VERSION 5.8 ;
BUSBITCHARS "[]" ;
DIVIDERCHAR "/" ;
UNITS
    DATABASE MICRONS 1000 ;
END UNITS

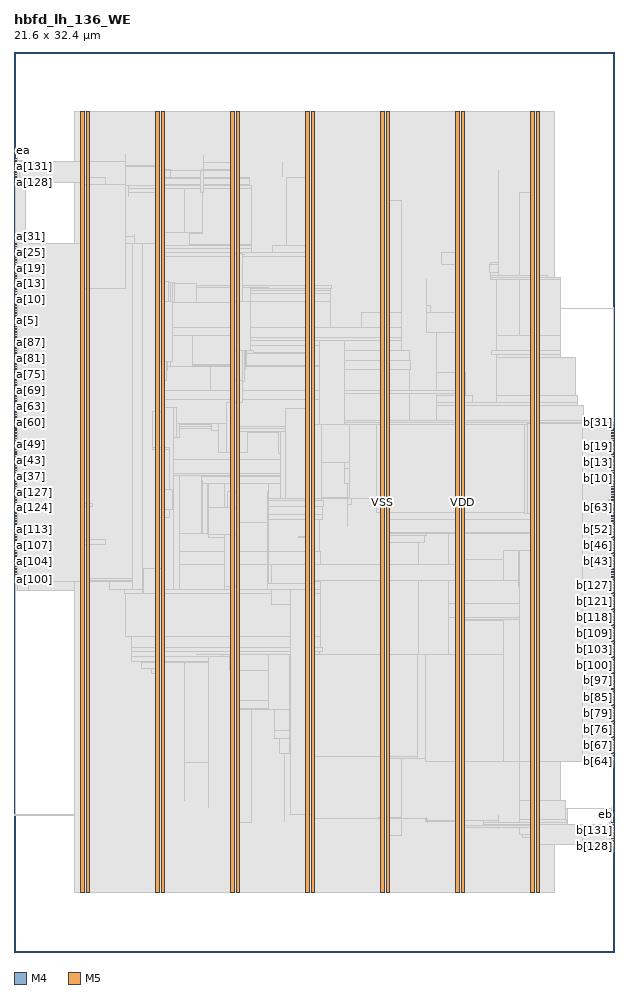
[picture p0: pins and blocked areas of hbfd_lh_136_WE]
MACRO hbfd_lh_136_WE
  FOREIGN hbfd_lh_136_WE 0 0 ;
  CLASS BLOCK ;
  SIZE 21.6 BY 32.4 ;
  PIN a[0]
    DIRECTION INPUT ;
    USE SIGNAL ;
    PORT
      LAYER M4 ;
        RECT  0 22.512 0.084 22.536 ;
    END
  END a[0]
  PIN a[100]
    DIRECTION INPUT ;
    USE SIGNAL ;
    PORT
      LAYER M4 ;
        RECT  0 13.68 0.084 13.704 ;
    END
  END a[100]
  PIN a[101]
    DIRECTION INPUT ;
    USE SIGNAL ;
    PORT
      LAYER M4 ;
        RECT  0 13.776 0.084 13.8 ;
    END
  END a[101]
  PIN a[102]
    DIRECTION INPUT ;
    USE SIGNAL ;
    PORT
      LAYER M4 ;
        RECT  0 13.872 0.084 13.896 ;
    END
  END a[102]
  PIN a[103]
    DIRECTION INPUT ;
    USE SIGNAL ;
    PORT
      LAYER M4 ;
        RECT  0 13.968 0.084 13.992 ;
    END
  END a[103]
  PIN a[104]
    DIRECTION INPUT ;
    USE SIGNAL ;
    PORT
      LAYER M4 ;
        RECT  0 14.064 0.084 14.088 ;
    END
  END a[104]
  PIN a[105]
    DIRECTION INPUT ;
    USE SIGNAL ;
    PORT
      LAYER M4 ;
        RECT  0 14.16 0.084 14.184 ;
    END
  END a[105]
  PIN a[106]
    DIRECTION INPUT ;
    USE SIGNAL ;
    PORT
      LAYER M4 ;
        RECT  0 14.256 0.084 14.28 ;
    END
  END a[106]
  PIN a[107]
    DIRECTION INPUT ;
    USE SIGNAL ;
    PORT
      LAYER M4 ;
        RECT  0 14.352 0.084 14.376 ;
    END
  END a[107]
  PIN a[108]
    DIRECTION INPUT ;
    USE SIGNAL ;
    PORT
      LAYER M4 ;
        RECT  0 14.448 0.084 14.472 ;
    END
  END a[108]
  PIN a[109]
    DIRECTION INPUT ;
    USE SIGNAL ;
    PORT
      LAYER M4 ;
        RECT  0 14.544 0.084 14.568 ;
    END
  END a[109]
  PIN a[10]
    DIRECTION INPUT ;
    USE SIGNAL ;
    PORT
      LAYER M4 ;
        RECT  0 23.472 0.084 23.496 ;
    END
  END a[10]
  PIN a[110]
    DIRECTION INPUT ;
    USE SIGNAL ;
    PORT
      LAYER M4 ;
        RECT  0 14.64 0.084 14.664 ;
    END
  END a[110]
  PIN a[111]
    DIRECTION INPUT ;
    USE SIGNAL ;
    PORT
      LAYER M4 ;
        RECT  0 14.736 0.084 14.76 ;
    END
  END a[111]
  PIN a[112]
    DIRECTION INPUT ;
    USE SIGNAL ;
    PORT
      LAYER M4 ;
        RECT  0 14.832 0.084 14.856 ;
    END
  END a[112]
  PIN a[113]
    DIRECTION INPUT ;
    USE SIGNAL ;
    PORT
      LAYER M4 ;
        RECT  0 14.928 0.084 14.952 ;
    END
  END a[113]
  PIN a[114]
    DIRECTION INPUT ;
    USE SIGNAL ;
    PORT
      LAYER M4 ;
        RECT  0 15.024 0.084 15.048 ;
    END
  END a[114]
  PIN a[115]
    DIRECTION INPUT ;
    USE SIGNAL ;
    PORT
      LAYER M4 ;
        RECT  0 15.12 0.084 15.144 ;
    END
  END a[115]
  PIN a[116]
    DIRECTION INPUT ;
    USE SIGNAL ;
    PORT
      LAYER M4 ;
        RECT  0 15.216 0.084 15.24 ;
    END
  END a[116]
  PIN a[117]
    DIRECTION INPUT ;
    USE SIGNAL ;
    PORT
      LAYER M4 ;
        RECT  0 15.312 0.084 15.336 ;
    END
  END a[117]
  PIN a[118]
    DIRECTION INPUT ;
    USE SIGNAL ;
    PORT
      LAYER M4 ;
        RECT  0 15.408 0.084 15.432 ;
    END
  END a[118]
  PIN a[119]
    DIRECTION INPUT ;
    USE SIGNAL ;
    PORT
      LAYER M4 ;
        RECT  0 15.504 0.084 15.528 ;
    END
  END a[119]
  PIN a[11]
    DIRECTION INPUT ;
    USE SIGNAL ;
    PORT
      LAYER M4 ;
        RECT  0 23.568 0.084 23.592 ;
    END
  END a[11]
  PIN a[120]
    DIRECTION INPUT ;
    USE SIGNAL ;
    PORT
      LAYER M4 ;
        RECT  0 15.6 0.084 15.624 ;
    END
  END a[120]
  PIN a[121]
    DIRECTION INPUT ;
    USE SIGNAL ;
    PORT
      LAYER M4 ;
        RECT  0 15.696 0.084 15.72 ;
    END
  END a[121]
  PIN a[122]
    DIRECTION INPUT ;
    USE SIGNAL ;
    PORT
      LAYER M4 ;
        RECT  0 15.792 0.084 15.816 ;
    END
  END a[122]
  PIN a[123]
    DIRECTION INPUT ;
    USE SIGNAL ;
    PORT
      LAYER M4 ;
        RECT  0 15.888 0.084 15.912 ;
    END
  END a[123]
  PIN a[124]
    DIRECTION INPUT ;
    USE SIGNAL ;
    PORT
      LAYER M4 ;
        RECT  0 15.984 0.084 16.008 ;
    END
  END a[124]
  PIN a[125]
    DIRECTION INPUT ;
    USE SIGNAL ;
    PORT
      LAYER M4 ;
        RECT  0 16.08 0.084 16.104 ;
    END
  END a[125]
  PIN a[126]
    DIRECTION INPUT ;
    USE SIGNAL ;
    PORT
      LAYER M4 ;
        RECT  0 16.176 0.084 16.2 ;
    END
  END a[126]
  PIN a[127]
    DIRECTION INPUT ;
    USE SIGNAL ;
    PORT
      LAYER M4 ;
        RECT  0 16.272 0.084 16.296 ;
    END
  END a[127]
  PIN a[128]
    DIRECTION INPUT ;
    USE SIGNAL ;
    PORT
      LAYER M4 ;
        RECT  0 27.696 0.084 27.72 ;
    END
  END a[128]
  PIN a[129]
    DIRECTION INPUT ;
    USE SIGNAL ;
    PORT
      LAYER M4 ;
        RECT  0 27.792 0.084 27.816 ;
    END
  END a[129]
  PIN a[12]
    DIRECTION INPUT ;
    USE SIGNAL ;
    PORT
      LAYER M4 ;
        RECT  0 23.664 0.084 23.688 ;
    END
  END a[12]
  PIN a[130]
    DIRECTION INPUT ;
    USE SIGNAL ;
    PORT
      LAYER M4 ;
        RECT  0 27.888 0.084 27.912 ;
    END
  END a[130]
  PIN a[131]
    DIRECTION INPUT ;
    USE SIGNAL ;
    PORT
      LAYER M4 ;
        RECT  0 27.984 0.084 28.008 ;
    END
  END a[131]
  PIN a[132]
    DIRECTION INPUT ;
    USE SIGNAL ;
    PORT
      LAYER M4 ;
        RECT  0 28.08 0.084 28.104 ;
    END
  END a[132]
  PIN a[133]
    DIRECTION INPUT ;
    USE SIGNAL ;
    PORT
      LAYER M4 ;
        RECT  0 28.176 0.084 28.2 ;
    END
  END a[133]
  PIN a[134]
    DIRECTION INPUT ;
    USE SIGNAL ;
    PORT
      LAYER M4 ;
        RECT  0 28.272 0.084 28.296 ;
    END
  END a[134]
  PIN a[135]
    DIRECTION INPUT ;
    USE SIGNAL ;
    PORT
      LAYER M4 ;
        RECT  0 28.368 0.084 28.392 ;
    END
  END a[135]
  PIN a[13]
    DIRECTION INPUT ;
    USE SIGNAL ;
    PORT
      LAYER M4 ;
        RECT  0 23.76 0.084 23.784 ;
    END
  END a[13]
  PIN a[14]
    DIRECTION INPUT ;
    USE SIGNAL ;
    PORT
      LAYER M4 ;
        RECT  0 23.856 0.084 23.88 ;
    END
  END a[14]
  PIN a[15]
    DIRECTION INPUT ;
    USE SIGNAL ;
    PORT
      LAYER M4 ;
        RECT  0 23.952 0.084 23.976 ;
    END
  END a[15]
  PIN a[16]
    DIRECTION INPUT ;
    USE SIGNAL ;
    PORT
      LAYER M4 ;
        RECT  0 24.048 0.084 24.072 ;
    END
  END a[16]
  PIN a[17]
    DIRECTION INPUT ;
    USE SIGNAL ;
    PORT
      LAYER M4 ;
        RECT  0 24.144 0.084 24.168 ;
    END
  END a[17]
  PIN a[18]
    DIRECTION INPUT ;
    USE SIGNAL ;
    PORT
      LAYER M4 ;
        RECT  0 24.24 0.084 24.264 ;
    END
  END a[18]
  PIN a[19]
    DIRECTION INPUT ;
    USE SIGNAL ;
    PORT
      LAYER M4 ;
        RECT  0 24.336 0.084 24.36 ;
    END
  END a[19]
  PIN a[1]
    DIRECTION INPUT ;
    USE SIGNAL ;
    PORT
      LAYER M4 ;
        RECT  0 22.608 0.084 22.632 ;
    END
  END a[1]
  PIN a[20]
    DIRECTION INPUT ;
    USE SIGNAL ;
    PORT
      LAYER M4 ;
        RECT  0 24.432 0.084 24.456 ;
    END
  END a[20]
  PIN a[21]
    DIRECTION INPUT ;
    USE SIGNAL ;
    PORT
      LAYER M4 ;
        RECT  0 24.528 0.084 24.552 ;
    END
  END a[21]
  PIN a[22]
    DIRECTION INPUT ;
    USE SIGNAL ;
    PORT
      LAYER M4 ;
        RECT  0 24.624 0.084 24.648 ;
    END
  END a[22]
  PIN a[23]
    DIRECTION INPUT ;
    USE SIGNAL ;
    PORT
      LAYER M4 ;
        RECT  0 24.72 0.084 24.744 ;
    END
  END a[23]
  PIN a[24]
    DIRECTION INPUT ;
    USE SIGNAL ;
    PORT
      LAYER M4 ;
        RECT  0 24.816 0.084 24.84 ;
    END
  END a[24]
  PIN a[25]
    DIRECTION INPUT ;
    USE SIGNAL ;
    PORT
      LAYER M4 ;
        RECT  0 24.912 0.084 24.936 ;
    END
  END a[25]
  PIN a[26]
    DIRECTION INPUT ;
    USE SIGNAL ;
    PORT
      LAYER M4 ;
        RECT  0 25.008 0.084 25.032 ;
    END
  END a[26]
  PIN a[27]
    DIRECTION INPUT ;
    USE SIGNAL ;
    PORT
      LAYER M4 ;
        RECT  0 25.104 0.084 25.128 ;
    END
  END a[27]
  PIN a[28]
    DIRECTION INPUT ;
    USE SIGNAL ;
    PORT
      LAYER M4 ;
        RECT  0 25.2 0.084 25.224 ;
    END
  END a[28]
  PIN a[29]
    DIRECTION INPUT ;
    USE SIGNAL ;
    PORT
      LAYER M4 ;
        RECT  0 25.296 0.084 25.32 ;
    END
  END a[29]
  PIN a[2]
    DIRECTION INPUT ;
    USE SIGNAL ;
    PORT
      LAYER M4 ;
        RECT  0 22.704 0.084 22.728 ;
    END
  END a[2]
  PIN a[30]
    DIRECTION INPUT ;
    USE SIGNAL ;
    PORT
      LAYER M4 ;
        RECT  0 25.392 0.084 25.416 ;
    END
  END a[30]
  PIN a[31]
    DIRECTION INPUT ;
    USE SIGNAL ;
    PORT
      LAYER M4 ;
        RECT  0 25.488 0.084 25.512 ;
    END
  END a[31]
  PIN a[32]
    DIRECTION INPUT ;
    USE SIGNAL ;
    PORT
      LAYER M4 ;
        RECT  0 16.368 0.084 16.392 ;
    END
  END a[32]
  PIN a[33]
    DIRECTION INPUT ;
    USE SIGNAL ;
    PORT
      LAYER M4 ;
        RECT  0 16.464 0.084 16.488 ;
    END
  END a[33]
  PIN a[34]
    DIRECTION INPUT ;
    USE SIGNAL ;
    PORT
      LAYER M4 ;
        RECT  0 16.56 0.084 16.584 ;
    END
  END a[34]
  PIN a[35]
    DIRECTION INPUT ;
    USE SIGNAL ;
    PORT
      LAYER M4 ;
        RECT  0 16.656 0.084 16.68 ;
    END
  END a[35]
  PIN a[36]
    DIRECTION INPUT ;
    USE SIGNAL ;
    PORT
      LAYER M4 ;
        RECT  0 16.752 0.084 16.776 ;
    END
  END a[36]
  PIN a[37]
    DIRECTION INPUT ;
    USE SIGNAL ;
    PORT
      LAYER M4 ;
        RECT  0 16.848 0.084 16.872 ;
    END
  END a[37]
  PIN a[38]
    DIRECTION INPUT ;
    USE SIGNAL ;
    PORT
      LAYER M4 ;
        RECT  0 16.944 0.084 16.968 ;
    END
  END a[38]
  PIN a[39]
    DIRECTION INPUT ;
    USE SIGNAL ;
    PORT
      LAYER M4 ;
        RECT  0 17.04 0.084 17.064 ;
    END
  END a[39]
  PIN a[3]
    DIRECTION INPUT ;
    USE SIGNAL ;
    PORT
      LAYER M4 ;
        RECT  0 22.8 0.084 22.824 ;
    END
  END a[3]
  PIN a[40]
    DIRECTION INPUT ;
    USE SIGNAL ;
    PORT
      LAYER M4 ;
        RECT  0 17.136 0.084 17.16 ;
    END
  END a[40]
  PIN a[41]
    DIRECTION INPUT ;
    USE SIGNAL ;
    PORT
      LAYER M4 ;
        RECT  0 17.232 0.084 17.256 ;
    END
  END a[41]
  PIN a[42]
    DIRECTION INPUT ;
    USE SIGNAL ;
    PORT
      LAYER M4 ;
        RECT  0 17.328 0.084 17.352 ;
    END
  END a[42]
  PIN a[43]
    DIRECTION INPUT ;
    USE SIGNAL ;
    PORT
      LAYER M4 ;
        RECT  0 17.424 0.084 17.448 ;
    END
  END a[43]
  PIN a[44]
    DIRECTION INPUT ;
    USE SIGNAL ;
    PORT
      LAYER M4 ;
        RECT  0 17.52 0.084 17.544 ;
    END
  END a[44]
  PIN a[45]
    DIRECTION INPUT ;
    USE SIGNAL ;
    PORT
      LAYER M4 ;
        RECT  0 17.616 0.084 17.64 ;
    END
  END a[45]
  PIN a[46]
    DIRECTION INPUT ;
    USE SIGNAL ;
    PORT
      LAYER M4 ;
        RECT  0 17.712 0.084 17.736 ;
    END
  END a[46]
  PIN a[47]
    DIRECTION INPUT ;
    USE SIGNAL ;
    PORT
      LAYER M4 ;
        RECT  0 17.808 0.084 17.832 ;
    END
  END a[47]
  PIN a[48]
    DIRECTION INPUT ;
    USE SIGNAL ;
    PORT
      LAYER M4 ;
        RECT  0 17.904 0.084 17.928 ;
    END
  END a[48]
  PIN a[49]
    DIRECTION INPUT ;
    USE SIGNAL ;
    PORT
      LAYER M4 ;
        RECT  0 18 0.084 18.024 ;
    END
  END a[49]
  PIN a[4]
    DIRECTION INPUT ;
    USE SIGNAL ;
    PORT
      LAYER M4 ;
        RECT  0 22.896 0.084 22.92 ;
    END
  END a[4]
  PIN a[50]
    DIRECTION INPUT ;
    USE SIGNAL ;
    PORT
      LAYER M4 ;
        RECT  0 18.096 0.084 18.12 ;
    END
  END a[50]
  PIN a[51]
    DIRECTION INPUT ;
    USE SIGNAL ;
    PORT
      LAYER M4 ;
        RECT  0 18.192 0.084 18.216 ;
    END
  END a[51]
  PIN a[52]
    DIRECTION INPUT ;
    USE SIGNAL ;
    PORT
      LAYER M4 ;
        RECT  0 18.288 0.084 18.312 ;
    END
  END a[52]
  PIN a[53]
    DIRECTION INPUT ;
    USE SIGNAL ;
    PORT
      LAYER M4 ;
        RECT  0 18.384 0.084 18.408 ;
    END
  END a[53]
  PIN a[54]
    DIRECTION INPUT ;
    USE SIGNAL ;
    PORT
      LAYER M4 ;
        RECT  0 18.48 0.084 18.504 ;
    END
  END a[54]
  PIN a[55]
    DIRECTION INPUT ;
    USE SIGNAL ;
    PORT
      LAYER M4 ;
        RECT  0 18.576 0.084 18.6 ;
    END
  END a[55]
  PIN a[56]
    DIRECTION INPUT ;
    USE SIGNAL ;
    PORT
      LAYER M4 ;
        RECT  0 18.672 0.084 18.696 ;
    END
  END a[56]
  PIN a[57]
    DIRECTION INPUT ;
    USE SIGNAL ;
    PORT
      LAYER M4 ;
        RECT  0 18.768 0.084 18.792 ;
    END
  END a[57]
  PIN a[58]
    DIRECTION INPUT ;
    USE SIGNAL ;
    PORT
      LAYER M4 ;
        RECT  0 18.864 0.084 18.888 ;
    END
  END a[58]
  PIN a[59]
    DIRECTION INPUT ;
    USE SIGNAL ;
    PORT
      LAYER M4 ;
        RECT  0 18.96 0.084 18.984 ;
    END
  END a[59]
  PIN a[5]
    DIRECTION INPUT ;
    USE SIGNAL ;
    PORT
      LAYER M4 ;
        RECT  0 22.992 0.084 23.016 ;
    END
  END a[5]
  PIN a[60]
    DIRECTION INPUT ;
    USE SIGNAL ;
    PORT
      LAYER M4 ;
        RECT  0 19.056 0.084 19.08 ;
    END
  END a[60]
  PIN a[61]
    DIRECTION INPUT ;
    USE SIGNAL ;
    PORT
      LAYER M4 ;
        RECT  0 19.152 0.084 19.176 ;
    END
  END a[61]
  PIN a[62]
    DIRECTION INPUT ;
    USE SIGNAL ;
    PORT
      LAYER M4 ;
        RECT  0 19.248 0.084 19.272 ;
    END
  END a[62]
  PIN a[63]
    DIRECTION INPUT ;
    USE SIGNAL ;
    PORT
      LAYER M4 ;
        RECT  0 19.344 0.084 19.368 ;
    END
  END a[63]
  PIN a[64]
    DIRECTION INPUT ;
    USE SIGNAL ;
    PORT
      LAYER M4 ;
        RECT  0 19.44 0.084 19.464 ;
    END
  END a[64]
  PIN a[65]
    DIRECTION INPUT ;
    USE SIGNAL ;
    PORT
      LAYER M4 ;
        RECT  0 19.536 0.084 19.56 ;
    END
  END a[65]
  PIN a[66]
    DIRECTION INPUT ;
    USE SIGNAL ;
    PORT
      LAYER M4 ;
        RECT  0 19.632 0.084 19.656 ;
    END
  END a[66]
  PIN a[67]
    DIRECTION INPUT ;
    USE SIGNAL ;
    PORT
      LAYER M4 ;
        RECT  0 19.728 0.084 19.752 ;
    END
  END a[67]
  PIN a[68]
    DIRECTION INPUT ;
    USE SIGNAL ;
    PORT
      LAYER M4 ;
        RECT  0 19.824 0.084 19.848 ;
    END
  END a[68]
  PIN a[69]
    DIRECTION INPUT ;
    USE SIGNAL ;
    PORT
      LAYER M4 ;
        RECT  0 19.92 0.084 19.944 ;
    END
  END a[69]
  PIN a[6]
    DIRECTION INPUT ;
    USE SIGNAL ;
    PORT
      LAYER M4 ;
        RECT  0 23.088 0.084 23.112 ;
    END
  END a[6]
  PIN a[70]
    DIRECTION INPUT ;
    USE SIGNAL ;
    PORT
      LAYER M4 ;
        RECT  0 20.016 0.084 20.04 ;
    END
  END a[70]
  PIN a[71]
    DIRECTION INPUT ;
    USE SIGNAL ;
    PORT
      LAYER M4 ;
        RECT  0 20.112 0.084 20.136 ;
    END
  END a[71]
  PIN a[72]
    DIRECTION INPUT ;
    USE SIGNAL ;
    PORT
      LAYER M4 ;
        RECT  0 20.208 0.084 20.232 ;
    END
  END a[72]
  PIN a[73]
    DIRECTION INPUT ;
    USE SIGNAL ;
    PORT
      LAYER M4 ;
        RECT  0 20.304 0.084 20.328 ;
    END
  END a[73]
  PIN a[74]
    DIRECTION INPUT ;
    USE SIGNAL ;
    PORT
      LAYER M4 ;
        RECT  0 20.4 0.084 20.424 ;
    END
  END a[74]
  PIN a[75]
    DIRECTION INPUT ;
    USE SIGNAL ;
    PORT
      LAYER M4 ;
        RECT  0 20.496 0.084 20.52 ;
    END
  END a[75]
  PIN a[76]
    DIRECTION INPUT ;
    USE SIGNAL ;
    PORT
      LAYER M4 ;
        RECT  0 20.592 0.084 20.616 ;
    END
  END a[76]
  PIN a[77]
    DIRECTION INPUT ;
    USE SIGNAL ;
    PORT
      LAYER M4 ;
        RECT  0 20.688 0.084 20.712 ;
    END
  END a[77]
  PIN a[78]
    DIRECTION INPUT ;
    USE SIGNAL ;
    PORT
      LAYER M4 ;
        RECT  0 20.784 0.084 20.808 ;
    END
  END a[78]
  PIN a[79]
    DIRECTION INPUT ;
    USE SIGNAL ;
    PORT
      LAYER M4 ;
        RECT  0 20.88 0.084 20.904 ;
    END
  END a[79]
  PIN a[7]
    DIRECTION INPUT ;
    USE SIGNAL ;
    PORT
      LAYER M4 ;
        RECT  0 23.184 0.084 23.208 ;
    END
  END a[7]
  PIN a[80]
    DIRECTION INPUT ;
    USE SIGNAL ;
    PORT
      LAYER M4 ;
        RECT  0 20.976 0.084 21 ;
    END
  END a[80]
  PIN a[81]
    DIRECTION INPUT ;
    USE SIGNAL ;
    PORT
      LAYER M4 ;
        RECT  0 21.072 0.084 21.096 ;
    END
  END a[81]
  PIN a[82]
    DIRECTION INPUT ;
    USE SIGNAL ;
    PORT
      LAYER M4 ;
        RECT  0 21.168 0.084 21.192 ;
    END
  END a[82]
  PIN a[83]
    DIRECTION INPUT ;
    USE SIGNAL ;
    PORT
      LAYER M4 ;
        RECT  0 21.264 0.084 21.288 ;
    END
  END a[83]
  PIN a[84]
    DIRECTION INPUT ;
    USE SIGNAL ;
    PORT
      LAYER M4 ;
        RECT  0 21.36 0.084 21.384 ;
    END
  END a[84]
  PIN a[85]
    DIRECTION INPUT ;
    USE SIGNAL ;
    PORT
      LAYER M4 ;
        RECT  0 21.456 0.084 21.48 ;
    END
  END a[85]
  PIN a[86]
    DIRECTION INPUT ;
    USE SIGNAL ;
    PORT
      LAYER M4 ;
        RECT  0 21.552 0.084 21.576 ;
    END
  END a[86]
  PIN a[87]
    DIRECTION INPUT ;
    USE SIGNAL ;
    PORT
      LAYER M4 ;
        RECT  0 21.648 0.084 21.672 ;
    END
  END a[87]
  PIN a[88]
    DIRECTION INPUT ;
    USE SIGNAL ;
    PORT
      LAYER M4 ;
        RECT  0 21.744 0.084 21.768 ;
    END
  END a[88]
  PIN a[89]
    DIRECTION INPUT ;
    USE SIGNAL ;
    PORT
      LAYER M4 ;
        RECT  0 21.84 0.084 21.864 ;
    END
  END a[89]
  PIN a[8]
    DIRECTION INPUT ;
    USE SIGNAL ;
    PORT
      LAYER M4 ;
        RECT  0 23.28 0.084 23.304 ;
    END
  END a[8]
  PIN a[90]
    DIRECTION INPUT ;
    USE SIGNAL ;
    PORT
      LAYER M4 ;
        RECT  0 21.936 0.084 21.96 ;
    END
  END a[90]
  PIN a[91]
    DIRECTION INPUT ;
    USE SIGNAL ;
    PORT
      LAYER M4 ;
        RECT  0 22.032 0.084 22.056 ;
    END
  END a[91]
  PIN a[92]
    DIRECTION INPUT ;
    USE SIGNAL ;
    PORT
      LAYER M4 ;
        RECT  0 22.128 0.084 22.152 ;
    END
  END a[92]
  PIN a[93]
    DIRECTION INPUT ;
    USE SIGNAL ;
    PORT
      LAYER M4 ;
        RECT  0 22.224 0.084 22.248 ;
    END
  END a[93]
  PIN a[94]
    DIRECTION INPUT ;
    USE SIGNAL ;
    PORT
      LAYER M4 ;
        RECT  0 22.32 0.084 22.344 ;
    END
  END a[94]
  PIN a[95]
    DIRECTION INPUT ;
    USE SIGNAL ;
    PORT
      LAYER M4 ;
        RECT  0 22.416 0.084 22.44 ;
    END
  END a[95]
  PIN a[96]
    DIRECTION INPUT ;
    USE SIGNAL ;
    PORT
      LAYER M4 ;
        RECT  0 13.296 0.084 13.32 ;
    END
  END a[96]
  PIN a[97]
    DIRECTION INPUT ;
    USE SIGNAL ;
    PORT
      LAYER M4 ;
        RECT  0 13.392 0.084 13.416 ;
    END
  END a[97]
  PIN a[98]
    DIRECTION INPUT ;
    USE SIGNAL ;
    PORT
      LAYER M4 ;
        RECT  0 13.488 0.084 13.512 ;
    END
  END a[98]
  PIN a[99]
    DIRECTION INPUT ;
    USE SIGNAL ;
    PORT
      LAYER M4 ;
        RECT  0 13.584 0.084 13.608 ;
    END
  END a[99]
  PIN a[9]
    DIRECTION INPUT ;
    USE SIGNAL ;
    PORT
      LAYER M4 ;
        RECT  0 23.376 0.084 23.4 ;
    END
  END a[9]
  PIN b[0]
    DIRECTION OUTPUT ;
    USE SIGNAL ;
    PORT
      LAYER M4 ;
        RECT  21.516 16.08 21.6 16.104 ;
    END
  END b[0]
  PIN b[100]
    DIRECTION OUTPUT ;
    USE SIGNAL ;
    PORT
      LAYER M4 ;
        RECT  21.516 10.32 21.6 10.344 ;
    END
  END b[100]
  PIN b[101]
    DIRECTION OUTPUT ;
    USE SIGNAL ;
    PORT
      LAYER M4 ;
        RECT  21.516 10.416 21.6 10.44 ;
    END
  END b[101]
  PIN b[102]
    DIRECTION OUTPUT ;
    USE SIGNAL ;
    PORT
      LAYER M4 ;
        RECT  21.516 10.512 21.6 10.536 ;
    END
  END b[102]
  PIN b[103]
    DIRECTION OUTPUT ;
    USE SIGNAL ;
    PORT
      LAYER M4 ;
        RECT  21.516 10.608 21.6 10.632 ;
    END
  END b[103]
  PIN b[104]
    DIRECTION OUTPUT ;
    USE SIGNAL ;
    PORT
      LAYER M4 ;
        RECT  21.516 10.704 21.6 10.728 ;
    END
  END b[104]
  PIN b[105]
    DIRECTION OUTPUT ;
    USE SIGNAL ;
    PORT
      LAYER M4 ;
        RECT  21.516 10.8 21.6 10.824 ;
    END
  END b[105]
  PIN b[106]
    DIRECTION OUTPUT ;
    USE SIGNAL ;
    PORT
      LAYER M4 ;
        RECT  21.516 10.896 21.6 10.92 ;
    END
  END b[106]
  PIN b[107]
    DIRECTION OUTPUT ;
    USE SIGNAL ;
    PORT
      LAYER M4 ;
        RECT  21.516 10.992 21.6 11.016 ;
    END
  END b[107]
  PIN b[108]
    DIRECTION OUTPUT ;
    USE SIGNAL ;
    PORT
      LAYER M4 ;
        RECT  21.516 11.088 21.6 11.112 ;
    END
  END b[108]
  PIN b[109]
    DIRECTION OUTPUT ;
    USE SIGNAL ;
    PORT
      LAYER M4 ;
        RECT  21.516 11.184 21.6 11.208 ;
    END
  END b[109]
  PIN b[10]
    DIRECTION OUTPUT ;
    USE SIGNAL ;
    PORT
      LAYER M4 ;
        RECT  21.516 17.04 21.6 17.064 ;
    END
  END b[10]
  PIN b[110]
    DIRECTION OUTPUT ;
    USE SIGNAL ;
    PORT
      LAYER M4 ;
        RECT  21.516 11.28 21.6 11.304 ;
    END
  END b[110]
  PIN b[111]
    DIRECTION OUTPUT ;
    USE SIGNAL ;
    PORT
      LAYER M4 ;
        RECT  21.516 11.376 21.6 11.4 ;
    END
  END b[111]
  PIN b[112]
    DIRECTION OUTPUT ;
    USE SIGNAL ;
    PORT
      LAYER M4 ;
        RECT  21.516 11.472 21.6 11.496 ;
    END
  END b[112]
  PIN b[113]
    DIRECTION OUTPUT ;
    USE SIGNAL ;
    PORT
      LAYER M4 ;
        RECT  21.516 11.568 21.6 11.592 ;
    END
  END b[113]
  PIN b[114]
    DIRECTION OUTPUT ;
    USE SIGNAL ;
    PORT
      LAYER M4 ;
        RECT  21.516 11.664 21.6 11.688 ;
    END
  END b[114]
  PIN b[115]
    DIRECTION OUTPUT ;
    USE SIGNAL ;
    PORT
      LAYER M4 ;
        RECT  21.516 11.76 21.6 11.784 ;
    END
  END b[115]
  PIN b[116]
    DIRECTION OUTPUT ;
    USE SIGNAL ;
    PORT
      LAYER M4 ;
        RECT  21.516 11.856 21.6 11.88 ;
    END
  END b[116]
  PIN b[117]
    DIRECTION OUTPUT ;
    USE SIGNAL ;
    PORT
      LAYER M4 ;
        RECT  21.516 11.952 21.6 11.976 ;
    END
  END b[117]
  PIN b[118]
    DIRECTION OUTPUT ;
    USE SIGNAL ;
    PORT
      LAYER M4 ;
        RECT  21.516 12.048 21.6 12.072 ;
    END
  END b[118]
  PIN b[119]
    DIRECTION OUTPUT ;
    USE SIGNAL ;
    PORT
      LAYER M4 ;
        RECT  21.516 12.144 21.6 12.168 ;
    END
  END b[119]
  PIN b[11]
    DIRECTION OUTPUT ;
    USE SIGNAL ;
    PORT
      LAYER M4 ;
        RECT  21.516 17.136 21.6 17.16 ;
    END
  END b[11]
  PIN b[120]
    DIRECTION OUTPUT ;
    USE SIGNAL ;
    PORT
      LAYER M4 ;
        RECT  21.516 12.24 21.6 12.264 ;
    END
  END b[120]
  PIN b[121]
    DIRECTION OUTPUT ;
    USE SIGNAL ;
    PORT
      LAYER M4 ;
        RECT  21.516 12.336 21.6 12.36 ;
    END
  END b[121]
  PIN b[122]
    DIRECTION OUTPUT ;
    USE SIGNAL ;
    PORT
      LAYER M4 ;
        RECT  21.516 12.432 21.6 12.456 ;
    END
  END b[122]
  PIN b[123]
    DIRECTION OUTPUT ;
    USE SIGNAL ;
    PORT
      LAYER M4 ;
        RECT  21.516 12.528 21.6 12.552 ;
    END
  END b[123]
  PIN b[124]
    DIRECTION OUTPUT ;
    USE SIGNAL ;
    PORT
      LAYER M4 ;
        RECT  21.516 12.624 21.6 12.648 ;
    END
  END b[124]
  PIN b[125]
    DIRECTION OUTPUT ;
    USE SIGNAL ;
    PORT
      LAYER M4 ;
        RECT  21.516 12.72 21.6 12.744 ;
    END
  END b[125]
  PIN b[126]
    DIRECTION OUTPUT ;
    USE SIGNAL ;
    PORT
      LAYER M4 ;
        RECT  21.516 12.816 21.6 12.84 ;
    END
  END b[126]
  PIN b[127]
    DIRECTION OUTPUT ;
    USE SIGNAL ;
    PORT
      LAYER M4 ;
        RECT  21.516 12.912 21.6 12.936 ;
    END
  END b[127]
  PIN b[128]
    DIRECTION OUTPUT ;
    USE SIGNAL ;
    PORT
      LAYER M4 ;
        RECT  21.516 3.792 21.6 3.816 ;
    END
  END b[128]
  PIN b[129]
    DIRECTION OUTPUT ;
    USE SIGNAL ;
    PORT
      LAYER M4 ;
        RECT  21.516 3.888 21.6 3.912 ;
    END
  END b[129]
  PIN b[12]
    DIRECTION OUTPUT ;
    USE SIGNAL ;
    PORT
      LAYER M4 ;
        RECT  21.516 17.232 21.6 17.256 ;
    END
  END b[12]
  PIN b[130]
    DIRECTION OUTPUT ;
    USE SIGNAL ;
    PORT
      LAYER M4 ;
        RECT  21.516 3.984 21.6 4.008 ;
    END
  END b[130]
  PIN b[131]
    DIRECTION OUTPUT ;
    USE SIGNAL ;
    PORT
      LAYER M4 ;
        RECT  21.516 4.08 21.6 4.104 ;
    END
  END b[131]
  PIN b[132]
    DIRECTION OUTPUT ;
    USE SIGNAL ;
    PORT
      LAYER M4 ;
        RECT  21.516 4.176 21.6 4.2 ;
    END
  END b[132]
  PIN b[133]
    DIRECTION OUTPUT ;
    USE SIGNAL ;
    PORT
      LAYER M4 ;
        RECT  21.516 4.272 21.6 4.296 ;
    END
  END b[133]
  PIN b[134]
    DIRECTION OUTPUT ;
    USE SIGNAL ;
    PORT
      LAYER M4 ;
        RECT  21.516 4.368 21.6 4.392 ;
    END
  END b[134]
  PIN b[135]
    DIRECTION OUTPUT ;
    USE SIGNAL ;
    PORT
      LAYER M4 ;
        RECT  21.516 4.464 21.6 4.488 ;
    END
  END b[135]
  PIN b[13]
    DIRECTION OUTPUT ;
    USE SIGNAL ;
    PORT
      LAYER M4 ;
        RECT  21.516 17.328 21.6 17.352 ;
    END
  END b[13]
  PIN b[14]
    DIRECTION OUTPUT ;
    USE SIGNAL ;
    PORT
      LAYER M4 ;
        RECT  21.516 17.424 21.6 17.448 ;
    END
  END b[14]
  PIN b[15]
    DIRECTION OUTPUT ;
    USE SIGNAL ;
    PORT
      LAYER M4 ;
        RECT  21.516 17.52 21.6 17.544 ;
    END
  END b[15]
  PIN b[16]
    DIRECTION OUTPUT ;
    USE SIGNAL ;
    PORT
      LAYER M4 ;
        RECT  21.516 17.616 21.6 17.64 ;
    END
  END b[16]
  PIN b[17]
    DIRECTION OUTPUT ;
    USE SIGNAL ;
    PORT
      LAYER M4 ;
        RECT  21.516 17.712 21.6 17.736 ;
    END
  END b[17]
  PIN b[18]
    DIRECTION OUTPUT ;
    USE SIGNAL ;
    PORT
      LAYER M4 ;
        RECT  21.516 17.808 21.6 17.832 ;
    END
  END b[18]
  PIN b[19]
    DIRECTION OUTPUT ;
    USE SIGNAL ;
    PORT
      LAYER M4 ;
        RECT  21.516 17.904 21.6 17.928 ;
    END
  END b[19]
  PIN b[1]
    DIRECTION OUTPUT ;
    USE SIGNAL ;
    PORT
      LAYER M4 ;
        RECT  21.516 16.176 21.6 16.2 ;
    END
  END b[1]
  PIN b[20]
    DIRECTION OUTPUT ;
    USE SIGNAL ;
    PORT
      LAYER M4 ;
        RECT  21.516 18 21.6 18.024 ;
    END
  END b[20]
  PIN b[21]
    DIRECTION OUTPUT ;
    USE SIGNAL ;
    PORT
      LAYER M4 ;
        RECT  21.516 18.096 21.6 18.12 ;
    END
  END b[21]
  PIN b[22]
    DIRECTION OUTPUT ;
    USE SIGNAL ;
    PORT
      LAYER M4 ;
        RECT  21.516 18.192 21.6 18.216 ;
    END
  END b[22]
  PIN b[23]
    DIRECTION OUTPUT ;
    USE SIGNAL ;
    PORT
      LAYER M4 ;
        RECT  21.516 18.288 21.6 18.312 ;
    END
  END b[23]
  PIN b[24]
    DIRECTION OUTPUT ;
    USE SIGNAL ;
    PORT
      LAYER M4 ;
        RECT  21.516 18.384 21.6 18.408 ;
    END
  END b[24]
  PIN b[25]
    DIRECTION OUTPUT ;
    USE SIGNAL ;
    PORT
      LAYER M4 ;
        RECT  21.516 18.48 21.6 18.504 ;
    END
  END b[25]
  PIN b[26]
    DIRECTION OUTPUT ;
    USE SIGNAL ;
    PORT
      LAYER M4 ;
        RECT  21.516 18.576 21.6 18.6 ;
    END
  END b[26]
  PIN b[27]
    DIRECTION OUTPUT ;
    USE SIGNAL ;
    PORT
      LAYER M4 ;
        RECT  21.516 18.672 21.6 18.696 ;
    END
  END b[27]
  PIN b[28]
    DIRECTION OUTPUT ;
    USE SIGNAL ;
    PORT
      LAYER M4 ;
        RECT  21.516 18.768 21.6 18.792 ;
    END
  END b[28]
  PIN b[29]
    DIRECTION OUTPUT ;
    USE SIGNAL ;
    PORT
      LAYER M4 ;
        RECT  21.516 18.864 21.6 18.888 ;
    END
  END b[29]
  PIN b[2]
    DIRECTION OUTPUT ;
    USE SIGNAL ;
    PORT
      LAYER M4 ;
        RECT  21.516 16.272 21.6 16.296 ;
    END
  END b[2]
  PIN b[30]
    DIRECTION OUTPUT ;
    USE SIGNAL ;
    PORT
      LAYER M4 ;
        RECT  21.516 18.96 21.6 18.984 ;
    END
  END b[30]
  PIN b[31]
    DIRECTION OUTPUT ;
    USE SIGNAL ;
    PORT
      LAYER M4 ;
        RECT  21.516 19.056 21.6 19.08 ;
    END
  END b[31]
  PIN b[32]
    DIRECTION OUTPUT ;
    USE SIGNAL ;
    PORT
      LAYER M4 ;
        RECT  21.516 13.008 21.6 13.032 ;
    END
  END b[32]
  PIN b[33]
    DIRECTION OUTPUT ;
    USE SIGNAL ;
    PORT
      LAYER M4 ;
        RECT  21.516 13.104 21.6 13.128 ;
    END
  END b[33]
  PIN b[34]
    DIRECTION OUTPUT ;
    USE SIGNAL ;
    PORT
      LAYER M4 ;
        RECT  21.516 13.2 21.6 13.224 ;
    END
  END b[34]
  PIN b[35]
    DIRECTION OUTPUT ;
    USE SIGNAL ;
    PORT
      LAYER M4 ;
        RECT  21.516 13.296 21.6 13.32 ;
    END
  END b[35]
  PIN b[36]
    DIRECTION OUTPUT ;
    USE SIGNAL ;
    PORT
      LAYER M4 ;
        RECT  21.516 13.392 21.6 13.416 ;
    END
  END b[36]
  PIN b[37]
    DIRECTION OUTPUT ;
    USE SIGNAL ;
    PORT
      LAYER M4 ;
        RECT  21.516 13.488 21.6 13.512 ;
    END
  END b[37]
  PIN b[38]
    DIRECTION OUTPUT ;
    USE SIGNAL ;
    PORT
      LAYER M4 ;
        RECT  21.516 13.584 21.6 13.608 ;
    END
  END b[38]
  PIN b[39]
    DIRECTION OUTPUT ;
    USE SIGNAL ;
    PORT
      LAYER M4 ;
        RECT  21.516 13.68 21.6 13.704 ;
    END
  END b[39]
  PIN b[3]
    DIRECTION OUTPUT ;
    USE SIGNAL ;
    PORT
      LAYER M4 ;
        RECT  21.516 16.368 21.6 16.392 ;
    END
  END b[3]
  PIN b[40]
    DIRECTION OUTPUT ;
    USE SIGNAL ;
    PORT
      LAYER M4 ;
        RECT  21.516 13.776 21.6 13.8 ;
    END
  END b[40]
  PIN b[41]
    DIRECTION OUTPUT ;
    USE SIGNAL ;
    PORT
      LAYER M4 ;
        RECT  21.516 13.872 21.6 13.896 ;
    END
  END b[41]
  PIN b[42]
    DIRECTION OUTPUT ;
    USE SIGNAL ;
    PORT
      LAYER M4 ;
        RECT  21.516 13.968 21.6 13.992 ;
    END
  END b[42]
  PIN b[43]
    DIRECTION OUTPUT ;
    USE SIGNAL ;
    PORT
      LAYER M4 ;
        RECT  21.516 14.064 21.6 14.088 ;
    END
  END b[43]
  PIN b[44]
    DIRECTION OUTPUT ;
    USE SIGNAL ;
    PORT
      LAYER M4 ;
        RECT  21.516 14.16 21.6 14.184 ;
    END
  END b[44]
  PIN b[45]
    DIRECTION OUTPUT ;
    USE SIGNAL ;
    PORT
      LAYER M4 ;
        RECT  21.516 14.256 21.6 14.28 ;
    END
  END b[45]
  PIN b[46]
    DIRECTION OUTPUT ;
    USE SIGNAL ;
    PORT
      LAYER M4 ;
        RECT  21.516 14.352 21.6 14.376 ;
    END
  END b[46]
  PIN b[47]
    DIRECTION OUTPUT ;
    USE SIGNAL ;
    PORT
      LAYER M4 ;
        RECT  21.516 14.448 21.6 14.472 ;
    END
  END b[47]
  PIN b[48]
    DIRECTION OUTPUT ;
    USE SIGNAL ;
    PORT
      LAYER M4 ;
        RECT  21.516 14.544 21.6 14.568 ;
    END
  END b[48]
  PIN b[49]
    DIRECTION OUTPUT ;
    USE SIGNAL ;
    PORT
      LAYER M4 ;
        RECT  21.516 14.64 21.6 14.664 ;
    END
  END b[49]
  PIN b[4]
    DIRECTION OUTPUT ;
    USE SIGNAL ;
    PORT
      LAYER M4 ;
        RECT  21.516 16.464 21.6 16.488 ;
    END
  END b[4]
  PIN b[50]
    DIRECTION OUTPUT ;
    USE SIGNAL ;
    PORT
      LAYER M4 ;
        RECT  21.516 14.736 21.6 14.76 ;
    END
  END b[50]
  PIN b[51]
    DIRECTION OUTPUT ;
    USE SIGNAL ;
    PORT
      LAYER M4 ;
        RECT  21.516 14.832 21.6 14.856 ;
    END
  END b[51]
  PIN b[52]
    DIRECTION OUTPUT ;
    USE SIGNAL ;
    PORT
      LAYER M4 ;
        RECT  21.516 14.928 21.6 14.952 ;
    END
  END b[52]
  PIN b[53]
    DIRECTION OUTPUT ;
    USE SIGNAL ;
    PORT
      LAYER M4 ;
        RECT  21.516 15.024 21.6 15.048 ;
    END
  END b[53]
  PIN b[54]
    DIRECTION OUTPUT ;
    USE SIGNAL ;
    PORT
      LAYER M4 ;
        RECT  21.516 15.12 21.6 15.144 ;
    END
  END b[54]
  PIN b[55]
    DIRECTION OUTPUT ;
    USE SIGNAL ;
    PORT
      LAYER M4 ;
        RECT  21.516 15.216 21.6 15.24 ;
    END
  END b[55]
  PIN b[56]
    DIRECTION OUTPUT ;
    USE SIGNAL ;
    PORT
      LAYER M4 ;
        RECT  21.516 15.312 21.6 15.336 ;
    END
  END b[56]
  PIN b[57]
    DIRECTION OUTPUT ;
    USE SIGNAL ;
    PORT
      LAYER M4 ;
        RECT  21.516 15.408 21.6 15.432 ;
    END
  END b[57]
  PIN b[58]
    DIRECTION OUTPUT ;
    USE SIGNAL ;
    PORT
      LAYER M4 ;
        RECT  21.516 15.504 21.6 15.528 ;
    END
  END b[58]
  PIN b[59]
    DIRECTION OUTPUT ;
    USE SIGNAL ;
    PORT
      LAYER M4 ;
        RECT  21.516 15.6 21.6 15.624 ;
    END
  END b[59]
  PIN b[5]
    DIRECTION OUTPUT ;
    USE SIGNAL ;
    PORT
      LAYER M4 ;
        RECT  21.516 16.56 21.6 16.584 ;
    END
  END b[5]
  PIN b[60]
    DIRECTION OUTPUT ;
    USE SIGNAL ;
    PORT
      LAYER M4 ;
        RECT  21.516 15.696 21.6 15.72 ;
    END
  END b[60]
  PIN b[61]
    DIRECTION OUTPUT ;
    USE SIGNAL ;
    PORT
      LAYER M4 ;
        RECT  21.516 15.792 21.6 15.816 ;
    END
  END b[61]
  PIN b[62]
    DIRECTION OUTPUT ;
    USE SIGNAL ;
    PORT
      LAYER M4 ;
        RECT  21.516 15.888 21.6 15.912 ;
    END
  END b[62]
  PIN b[63]
    DIRECTION OUTPUT ;
    USE SIGNAL ;
    PORT
      LAYER M4 ;
        RECT  21.516 15.984 21.6 16.008 ;
    END
  END b[63]
  PIN b[64]
    DIRECTION OUTPUT ;
    USE SIGNAL ;
    PORT
      LAYER M4 ;
        RECT  21.516 6.864 21.6 6.888 ;
    END
  END b[64]
  PIN b[65]
    DIRECTION OUTPUT ;
    USE SIGNAL ;
    PORT
      LAYER M4 ;
        RECT  21.516 6.96 21.6 6.984 ;
    END
  END b[65]
  PIN b[66]
    DIRECTION OUTPUT ;
    USE SIGNAL ;
    PORT
      LAYER M4 ;
        RECT  21.516 7.056 21.6 7.08 ;
    END
  END b[66]
  PIN b[67]
    DIRECTION OUTPUT ;
    USE SIGNAL ;
    PORT
      LAYER M4 ;
        RECT  21.516 7.152 21.6 7.176 ;
    END
  END b[67]
  PIN b[68]
    DIRECTION OUTPUT ;
    USE SIGNAL ;
    PORT
      LAYER M4 ;
        RECT  21.516 7.248 21.6 7.272 ;
    END
  END b[68]
  PIN b[69]
    DIRECTION OUTPUT ;
    USE SIGNAL ;
    PORT
      LAYER M4 ;
        RECT  21.516 7.344 21.6 7.368 ;
    END
  END b[69]
  PIN b[6]
    DIRECTION OUTPUT ;
    USE SIGNAL ;
    PORT
      LAYER M4 ;
        RECT  21.516 16.656 21.6 16.68 ;
    END
  END b[6]
  PIN b[70]
    DIRECTION OUTPUT ;
    USE SIGNAL ;
    PORT
      LAYER M4 ;
        RECT  21.516 7.44 21.6 7.464 ;
    END
  END b[70]
  PIN b[71]
    DIRECTION OUTPUT ;
    USE SIGNAL ;
    PORT
      LAYER M4 ;
        RECT  21.516 7.536 21.6 7.56 ;
    END
  END b[71]
  PIN b[72]
    DIRECTION OUTPUT ;
    USE SIGNAL ;
    PORT
      LAYER M4 ;
        RECT  21.516 7.632 21.6 7.656 ;
    END
  END b[72]
  PIN b[73]
    DIRECTION OUTPUT ;
    USE SIGNAL ;
    PORT
      LAYER M4 ;
        RECT  21.516 7.728 21.6 7.752 ;
    END
  END b[73]
  PIN b[74]
    DIRECTION OUTPUT ;
    USE SIGNAL ;
    PORT
      LAYER M4 ;
        RECT  21.516 7.824 21.6 7.848 ;
    END
  END b[74]
  PIN b[75]
    DIRECTION OUTPUT ;
    USE SIGNAL ;
    PORT
      LAYER M4 ;
        RECT  21.516 7.92 21.6 7.944 ;
    END
  END b[75]
  PIN b[76]
    DIRECTION OUTPUT ;
    USE SIGNAL ;
    PORT
      LAYER M4 ;
        RECT  21.516 8.016 21.6 8.04 ;
    END
  END b[76]
  PIN b[77]
    DIRECTION OUTPUT ;
    USE SIGNAL ;
    PORT
      LAYER M4 ;
        RECT  21.516 8.112 21.6 8.136 ;
    END
  END b[77]
  PIN b[78]
    DIRECTION OUTPUT ;
    USE SIGNAL ;
    PORT
      LAYER M4 ;
        RECT  21.516 8.208 21.6 8.232 ;
    END
  END b[78]
  PIN b[79]
    DIRECTION OUTPUT ;
    USE SIGNAL ;
    PORT
      LAYER M4 ;
        RECT  21.516 8.304 21.6 8.328 ;
    END
  END b[79]
  PIN b[7]
    DIRECTION OUTPUT ;
    USE SIGNAL ;
    PORT
      LAYER M4 ;
        RECT  21.516 16.752 21.6 16.776 ;
    END
  END b[7]
  PIN b[80]
    DIRECTION OUTPUT ;
    USE SIGNAL ;
    PORT
      LAYER M4 ;
        RECT  21.516 8.4 21.6 8.424 ;
    END
  END b[80]
  PIN b[81]
    DIRECTION OUTPUT ;
    USE SIGNAL ;
    PORT
      LAYER M4 ;
        RECT  21.516 8.496 21.6 8.52 ;
    END
  END b[81]
  PIN b[82]
    DIRECTION OUTPUT ;
    USE SIGNAL ;
    PORT
      LAYER M4 ;
        RECT  21.516 8.592 21.6 8.616 ;
    END
  END b[82]
  PIN b[83]
    DIRECTION OUTPUT ;
    USE SIGNAL ;
    PORT
      LAYER M4 ;
        RECT  21.516 8.688 21.6 8.712 ;
    END
  END b[83]
  PIN b[84]
    DIRECTION OUTPUT ;
    USE SIGNAL ;
    PORT
      LAYER M4 ;
        RECT  21.516 8.784 21.6 8.808 ;
    END
  END b[84]
  PIN b[85]
    DIRECTION OUTPUT ;
    USE SIGNAL ;
    PORT
      LAYER M4 ;
        RECT  21.516 8.88 21.6 8.904 ;
    END
  END b[85]
  PIN b[86]
    DIRECTION OUTPUT ;
    USE SIGNAL ;
    PORT
      LAYER M4 ;
        RECT  21.516 8.976 21.6 9 ;
    END
  END b[86]
  PIN b[87]
    DIRECTION OUTPUT ;
    USE SIGNAL ;
    PORT
      LAYER M4 ;
        RECT  21.516 9.072 21.6 9.096 ;
    END
  END b[87]
  PIN b[88]
    DIRECTION OUTPUT ;
    USE SIGNAL ;
    PORT
      LAYER M4 ;
        RECT  21.516 9.168 21.6 9.192 ;
    END
  END b[88]
  PIN b[89]
    DIRECTION OUTPUT ;
    USE SIGNAL ;
    PORT
      LAYER M4 ;
        RECT  21.516 9.264 21.6 9.288 ;
    END
  END b[89]
  PIN b[8]
    DIRECTION OUTPUT ;
    USE SIGNAL ;
    PORT
      LAYER M4 ;
        RECT  21.516 16.848 21.6 16.872 ;
    END
  END b[8]
  PIN b[90]
    DIRECTION OUTPUT ;
    USE SIGNAL ;
    PORT
      LAYER M4 ;
        RECT  21.516 9.36 21.6 9.384 ;
    END
  END b[90]
  PIN b[91]
    DIRECTION OUTPUT ;
    USE SIGNAL ;
    PORT
      LAYER M4 ;
        RECT  21.516 9.456 21.6 9.48 ;
    END
  END b[91]
  PIN b[92]
    DIRECTION OUTPUT ;
    USE SIGNAL ;
    PORT
      LAYER M4 ;
        RECT  21.516 9.552 21.6 9.576 ;
    END
  END b[92]
  PIN b[93]
    DIRECTION OUTPUT ;
    USE SIGNAL ;
    PORT
      LAYER M4 ;
        RECT  21.516 9.648 21.6 9.672 ;
    END
  END b[93]
  PIN b[94]
    DIRECTION OUTPUT ;
    USE SIGNAL ;
    PORT
      LAYER M4 ;
        RECT  21.516 9.744 21.6 9.768 ;
    END
  END b[94]
  PIN b[95]
    DIRECTION OUTPUT ;
    USE SIGNAL ;
    PORT
      LAYER M4 ;
        RECT  21.516 9.84 21.6 9.864 ;
    END
  END b[95]
  PIN b[96]
    DIRECTION OUTPUT ;
    USE SIGNAL ;
    PORT
      LAYER M4 ;
        RECT  21.516 9.936 21.6 9.96 ;
    END
  END b[96]
  PIN b[97]
    DIRECTION OUTPUT ;
    USE SIGNAL ;
    PORT
      LAYER M4 ;
        RECT  21.516 10.032 21.6 10.056 ;
    END
  END b[97]
  PIN b[98]
    DIRECTION OUTPUT ;
    USE SIGNAL ;
    PORT
      LAYER M4 ;
        RECT  21.516 10.128 21.6 10.152 ;
    END
  END b[98]
  PIN b[99]
    DIRECTION OUTPUT ;
    USE SIGNAL ;
    PORT
      LAYER M4 ;
        RECT  21.516 10.224 21.6 10.248 ;
    END
  END b[99]
  PIN b[9]
    DIRECTION OUTPUT ;
    USE SIGNAL ;
    PORT
      LAYER M4 ;
        RECT  21.516 16.944 21.6 16.968 ;
    END
  END b[9]
  PIN ck_o
    DIRECTION OUTPUT ;
    USE SIGNAL ;
    PORT
      LAYER M4 ;
        RECT  21.516 4.56 21.6 4.584 ;
    END
  END ck_o
  PIN ckf
    DIRECTION INPUT ;
    USE SIGNAL ;
    PORT
      LAYER M4 ;
        RECT  0 28.464 0.084 28.488 ;
    END
  END ckf
  PIN ea
    DIRECTION INPUT ;
    USE SIGNAL ;
    PORT
      LAYER M4 ;
        RECT  0 28.56 0.084 28.584 ;
    END
  END ea
  PIN eb
    DIRECTION OUTPUT ;
    USE SIGNAL ;
    PORT
      LAYER M4 ;
        RECT  21.516 4.656 21.6 4.68 ;
    END
  END eb
  PIN VDD
    DIRECTION INOUT ;
    USE POWER ;
    PORT
      LAYER M5 ;
        RECT  18.792 2.151 18.912 30.249 ;
        RECT  16.092 2.151 16.212 30.249 ;
        RECT  13.392 2.151 13.512 30.249 ;
        RECT  10.692 2.151 10.812 30.249 ;
        RECT  7.992 2.151 8.112 30.249 ;
        RECT  5.292 2.151 5.412 30.249 ;
        RECT  2.592 2.151 2.712 30.249 ;
    END
  END VDD
  PIN VSS
    DIRECTION INOUT ;
    USE GROUND ;
    PORT
      LAYER M5 ;
        RECT  18.6 2.137 18.72 30.263 ;
        RECT  15.9 2.137 16.02 30.263 ;
        RECT  13.2 2.137 13.32 30.263 ;
        RECT  10.5 2.137 10.62 30.263 ;
        RECT  7.8 2.137 7.92 30.263 ;
        RECT  5.1 2.137 5.22 30.263 ;
        RECT  2.4 2.137 2.52 30.263 ;
    END
  END VSS
  OBS
    LAYER RVTN ;
     RECT  2.16 2.16 19.44 2.295 ;
     RECT  2.16 2.565 19.44 2.835 ;
     RECT  2.16 3.105 19.44 3.375 ;
     RECT  2.16 3.645 19.44 3.915 ;
     RECT  2.16 4.185 19.44 4.455 ;
     RECT  2.16 4.725 19.44 4.995 ;
     RECT  2.16 5.265 19.44 5.535 ;
     RECT  2.16 5.805 19.44 6.075 ;
     RECT  2.16 6.345 19.44 6.615 ;
     RECT  2.16 6.885 19.44 7.155 ;
     RECT  2.16 7.425 19.44 7.695 ;
     RECT  2.16 7.965 19.44 8.235 ;
     RECT  2.16 8.505 19.44 8.775 ;
     RECT  2.16 9.045 19.44 9.315 ;
     RECT  2.16 9.585 19.44 9.855 ;
     RECT  2.16 10.125 19.44 10.395 ;
     RECT  2.16 10.665 19.44 10.935 ;
     RECT  2.16 11.205 19.44 11.475 ;
     RECT  2.16 11.745 19.44 12.015 ;
     RECT  2.16 12.285 19.44 12.555 ;
     RECT  2.16 12.825 19.44 13.095 ;
     RECT  2.16 13.365 19.44 13.635 ;
     RECT  2.16 13.905 19.44 14.175 ;
     RECT  2.16 14.445 19.44 14.715 ;
     RECT  2.16 14.985 19.44 15.255 ;
     RECT  2.16 15.525 19.44 15.795 ;
     RECT  2.16 16.065 19.44 16.335 ;
     RECT  2.16 16.605 19.44 16.875 ;
     RECT  2.16 17.145 19.44 17.415 ;
     RECT  2.16 17.685 19.44 17.955 ;
     RECT  2.16 18.225 19.44 18.495 ;
     RECT  2.16 18.765 19.44 19.035 ;
     RECT  2.16 19.305 19.44 19.575 ;
     RECT  2.16 19.845 19.44 20.115 ;
     RECT  2.16 20.385 19.44 20.655 ;
     RECT  2.16 20.925 19.44 21.195 ;
     RECT  2.16 21.465 19.44 21.735 ;
     RECT  2.16 22.005 19.44 22.275 ;
     RECT  2.16 22.545 19.44 22.815 ;
     RECT  2.16 23.085 19.44 23.355 ;
     RECT  2.16 23.625 19.44 23.895 ;
     RECT  2.16 24.165 19.44 24.435 ;
     RECT  2.16 24.705 19.44 24.975 ;
     RECT  2.16 25.245 19.44 25.515 ;
     RECT  2.16 25.785 19.44 26.055 ;
     RECT  2.16 26.325 19.44 26.595 ;
     RECT  2.16 26.865 19.44 27.135 ;
     RECT  2.16 27.405 19.44 27.675 ;
     RECT  2.16 27.945 19.44 28.215 ;
     RECT  2.16 28.485 19.44 28.755 ;
     RECT  2.16 29.025 19.44 29.295 ;
     RECT  2.16 29.565 19.44 29.835 ;
     RECT  2.16 30.105 19.44 30.24 ;
    LAYER RVTP ;
     RECT  2.16 2.295 19.44 2.565 ;
     RECT  2.16 2.835 19.44 3.105 ;
     RECT  2.16 3.375 19.44 3.645 ;
     RECT  2.16 3.915 19.44 4.185 ;
     RECT  2.16 4.455 19.44 4.725 ;
     RECT  2.16 4.995 19.44 5.265 ;
     RECT  2.16 5.535 19.44 5.805 ;
     RECT  2.16 6.075 19.44 6.345 ;
     RECT  2.16 6.615 19.44 6.885 ;
     RECT  2.16 7.155 19.44 7.425 ;
     RECT  2.16 7.695 19.44 7.965 ;
     RECT  2.16 8.235 19.44 8.505 ;
     RECT  2.16 8.775 19.44 9.045 ;
     RECT  2.16 9.315 19.44 9.585 ;
     RECT  2.16 9.855 19.44 10.125 ;
     RECT  2.16 10.395 19.44 10.665 ;
     RECT  2.16 10.935 19.44 11.205 ;
     RECT  2.16 11.475 19.44 11.745 ;
     RECT  2.16 12.015 19.44 12.285 ;
     RECT  2.16 12.555 19.44 12.825 ;
     RECT  2.16 13.095 19.44 13.365 ;
     RECT  2.16 13.635 19.44 13.905 ;
     RECT  2.16 14.175 19.44 14.445 ;
     RECT  2.16 14.715 19.44 14.985 ;
     RECT  2.16 15.255 19.44 15.525 ;
     RECT  2.16 15.795 19.44 16.065 ;
     RECT  2.16 16.335 19.44 16.605 ;
     RECT  2.16 16.875 19.44 17.145 ;
     RECT  2.16 17.415 19.44 17.685 ;
     RECT  2.16 17.955 19.44 18.225 ;
     RECT  2.16 18.495 19.44 18.765 ;
     RECT  2.16 19.035 19.44 19.305 ;
     RECT  2.16 19.575 19.44 19.845 ;
     RECT  2.16 20.115 19.44 20.385 ;
     RECT  2.16 20.655 19.44 20.925 ;
     RECT  2.16 21.195 19.44 21.465 ;
     RECT  2.16 21.735 19.44 22.005 ;
     RECT  2.16 22.275 19.44 22.545 ;
     RECT  2.16 22.815 19.44 23.085 ;
     RECT  2.16 23.355 19.44 23.625 ;
     RECT  2.16 23.895 19.44 24.165 ;
     RECT  2.16 24.435 19.44 24.705 ;
     RECT  2.16 24.975 19.44 25.245 ;
     RECT  2.16 25.515 19.44 25.785 ;
     RECT  2.16 26.055 19.44 26.325 ;
     RECT  2.16 26.595 19.44 26.865 ;
     RECT  2.16 27.135 19.44 27.405 ;
     RECT  2.16 27.675 19.44 27.945 ;
     RECT  2.16 28.215 19.44 28.485 ;
     RECT  2.16 28.755 19.44 29.025 ;
     RECT  2.16 29.295 19.44 29.565 ;
     RECT  2.16 29.835 19.44 30.105 ;
    LAYER M1 ;
     RECT  2.16 2.151 19.44 30.249 ;
    LAYER M2 ;
     RECT  0.031 28.152 0.103 28.17 ;
     RECT  0.103 17.622 0.139 17.64 ;
     RECT  0.103 27.918 0.175 28.17 ;
     RECT  0.103 16.146 0.203 16.164 ;
     RECT  0.103 18.81 0.203 19.368 ;
     RECT  0.103 21.591 0.203 21.798 ;
     RECT  0.103 25.29 0.203 25.308 ;
     RECT  0.203 18.972 0.239 19.368 ;
     RECT  0.175 27.918 0.419 28.476 ;
     RECT  0.103 13.032 0.535 15.174 ;
     RECT  0.139 17.046 0.535 17.64 ;
     RECT  0.239 19.314 0.535 19.368 ;
     RECT  0.103 23.166 0.563 23.184 ;
     RECT  0.031 4.932 2.16 4.95 ;
     RECT  0.535 13.032 2.16 15.48 ;
     RECT  0.535 17.046 2.16 18.18 ;
     RECT  0.535 19.314 2.16 19.836 ;
     RECT  0.535 22.212 2.16 22.23 ;
     RECT  0.419 27.918 2.16 27.936 ;
     RECT  2.16 2.151 19.44 30.249 ;
     RECT  19.44 24.246 19.679 24.264 ;
     RECT  19.44 19.476 19.751 21.384 ;
     RECT  19.751 20.826 19.787 21.384 ;
     RECT  19.44 4.086 19.859 5.454 ;
     RECT  19.44 11.25 19.895 18.144 ;
     RECT  19.859 4.086 19.931 5.184 ;
     RECT  19.895 11.25 19.931 13.014 ;
     RECT  19.895 13.986 19.931 18.144 ;
     RECT  19.787 21.366 20.219 21.384 ;
     RECT  19.751 19.476 20.291 20.034 ;
     RECT  20.291 19.476 20.327 19.674 ;
     RECT  19.931 14.076 20.435 18.144 ;
     RECT  20.435 14.076 20.471 14.094 ;
     RECT  20.435 14.958 20.471 18.144 ;
     RECT  19.931 4.086 20.507 4.284 ;
     RECT  20.471 14.958 20.507 15.552 ;
     RECT  20.471 16.506 20.507 16.632 ;
     RECT  20.327 19.656 20.507 19.674 ;
     RECT  19.931 11.286 20.543 12.816 ;
     RECT  20.471 17.388 21.235 18.144 ;
     RECT  21.235 17.388 21.335 18.72 ;
     RECT  20.507 16.506 21.379 16.524 ;
     RECT  19.44 10.026 21.415 10.494 ;
     RECT  20.543 11.376 21.415 12.654 ;
     RECT  21.379 16.146 21.415 16.524 ;
     RECT  21.335 17.388 21.415 17.829 ;
     RECT  21.415 11.376 21.443 13.194 ;
     RECT  20.507 4.266 21.479 4.284 ;
     RECT  21.443 11.376 21.479 11.574 ;
     RECT  20.507 14.958 21.479 15.282 ;
     RECT  21.415 16.146 21.479 17.829 ;
     RECT  19.931 5.166 21.515 5.184 ;
     RECT  21.415 7.866 21.515 8.154 ;
     RECT  21.415 9.171 21.515 10.494 ;
     RECT  21.479 11.52 21.515 11.538 ;
     RECT  21.443 12.366 21.515 13.194 ;
     RECT  21.479 14.958 21.515 14.976 ;
     RECT  21.479 16.506 21.515 16.794 ;
     RECT  21.335 18.702 21.515 18.72 ;
     RECT  21.479 17.811 21.587 17.829 ;
     RECT  19.44 23.166 21.587 23.184 ;
    LAYER M3 ;
     RECT  2.415 2.143 2.505 2.413 ;
     RECT  5.115 2.143 5.205 2.413 ;
     RECT  7.815 2.143 7.905 2.413 ;
     RECT  10.515 2.143 10.605 2.413 ;
     RECT  13.215 2.143 13.305 2.413 ;
     RECT  15.915 2.143 16.005 2.413 ;
     RECT  18.615 2.143 18.705 2.413 ;
     RECT  18.615 2.413 18.897 3.883 ;
     RECT  18.615 3.883 19.386 3.979 ;
     RECT  20.484 3.787 20.502 3.979 ;
     RECT  18.615 3.979 20.502 4.109 ;
     RECT  18.615 4.109 19.926 4.117 ;
     RECT  13.215 2.413 13.497 4.189 ;
     RECT  18.288 4.117 19.926 4.225 ;
     RECT  21.456 4.261 21.474 4.267 ;
     RECT  15.915 2.413 16.197 4.495 ;
     RECT  17.424 4.459 17.442 4.495 ;
     RECT  18.18 4.225 19.926 4.495 ;
     RECT  15.915 4.495 19.926 4.649 ;
     RECT  7.815 2.413 8.097 4.657 ;
     RECT  21.456 4.267 21.51 4.685 ;
     RECT  14.868 4.657 14.886 4.699 ;
     RECT  15.915 4.649 17.442 4.733 ;
     RECT  14.832 4.699 14.886 4.757 ;
     RECT  18.18 4.649 19.89 4.757 ;
     RECT  13.215 4.189 13.95 4.792 ;
     RECT  13.104 4.792 13.95 4.829 ;
     RECT  14.832 4.757 14.85 4.829 ;
     RECT  17.424 4.733 17.442 4.919 ;
     RECT  21.492 4.685 21.51 5.189 ;
     RECT  18.18 4.757 19.854 5.459 ;
     RECT  6.12 5.467 6.138 6.817 ;
     RECT  6.984 5.197 7.002 6.817 ;
     RECT  13.215 4.829 13.95 6.955 ;
     RECT  14.832 6.859 14.85 6.955 ;
     RECT  13.215 6.955 14.85 7.051 ;
     RECT  13.104 7.051 14.85 7.088 ;
     RECT  9.72 4.693 9.738 7.147 ;
     RECT  10.515 2.413 10.797 7.195 ;
     RECT  13.215 7.088 14.85 7.229 ;
     RECT  18.18 5.459 19.674 7.243 ;
     RECT  9.576 7.147 9.738 7.435 ;
     RECT  10.476 7.195 10.797 7.435 ;
     RECT  17.1 7.339 17.118 7.627 ;
     RECT  18.18 7.243 19.818 7.627 ;
     RECT  9.576 7.435 10.797 7.675 ;
     RECT  15.915 4.733 16.197 7.723 ;
     RECT  21.42 7.531 21.438 7.819 ;
     RECT  15.624 7.723 16.197 7.861 ;
     RECT  15.624 7.861 16.29 7.901 ;
     RECT  9.36 7.675 10.797 7.963 ;
     RECT  17.1 7.627 19.818 8.011 ;
     RECT  17.1 8.011 20.322 8.155 ;
     RECT  21.42 7.819 21.51 8.159 ;
     RECT  13.215 7.229 14.562 8.299 ;
     RECT  13.215 8.299 14.85 8.671 ;
     RECT  13.104 8.671 14.85 8.717 ;
     RECT  7.815 4.657 8.55 8.731 ;
     RECT  9.36 7.963 10.89 8.731 ;
     RECT  13.215 8.717 14.85 8.813 ;
     RECT  7.815 8.731 10.89 9.067 ;
     RECT  21.42 8.159 21.438 9.16 ;
     RECT  15.624 7.901 16.197 9.307 ;
     RECT  16.92 8.155 20.322 9.307 ;
     RECT  15.624 9.307 20.322 9.739 ;
     RECT  15.624 9.739 20.502 9.779 ;
     RECT  5.115 2.413 5.397 10.021 ;
     RECT  13.215 8.813 14.562 10.027 ;
     RECT  21.42 9.16 21.51 10.027 ;
     RECT  7.815 9.067 10.962 10.123 ;
     RECT  4.932 10.021 5.397 10.201 ;
     RECT  21.312 10.027 21.51 10.253 ;
     RECT  19.656 9.779 20.502 10.291 ;
     RECT  19.656 10.291 20.538 10.349 ;
     RECT  19.656 10.349 20.502 10.391 ;
     RECT  4.572 10.201 5.397 10.435 ;
     RECT  6.12 6.817 7.002 10.435 ;
     RECT  4.572 10.435 7.002 10.471 ;
     RECT  7.776 10.123 10.962 10.471 ;
     RECT  13.215 10.027 14.85 10.493 ;
     RECT  4.212 10.471 7.002 10.651 ;
     RECT  7.776 10.471 10.998 10.651 ;
     RECT  4.212 10.651 10.998 10.831 ;
     RECT  4.212 10.831 11.106 10.967 ;
     RECT  19.656 10.391 20.322 11.275 ;
     RECT  19.656 11.275 20.502 11.281 ;
     RECT  4.212 10.967 11.034 11.371 ;
     RECT  21.42 10.253 21.51 11.515 ;
     RECT  21.384 11.515 21.51 11.579 ;
     RECT  15.624 9.779 18.897 12.043 ;
     RECT  19.656 11.281 20.538 12.043 ;
     RECT  15.624 12.043 20.538 12.551 ;
     RECT  3.996 11.371 11.034 12.901 ;
     RECT  0.036 4.927 0.054 13.027 ;
     RECT  19.656 12.551 20.538 13.037 ;
     RECT  3.96 12.901 11.034 13.063 ;
     RECT  21.42 11.579 21.51 13.229 ;
     RECT  2.415 2.413 2.697 13.339 ;
     RECT  3.42 13.063 11.034 13.339 ;
     RECT  2.415 13.339 11.034 13.387 ;
     RECT  0.036 13.027 0.126 13.483 ;
     RECT  0.036 13.483 0.342 13.603 ;
     RECT  0.036 13.603 0.486 13.639 ;
     RECT  21.42 13.229 21.438 13.963 ;
     RECT  21.348 13.963 21.438 14.141 ;
     RECT  21.42 14.141 21.438 14.237 ;
     RECT  0.036 13.639 0.558 14.285 ;
     RECT  2.304 13.387 11.034 14.405 ;
     RECT  19.656 13.037 20.502 14.719 ;
     RECT  13.215 10.493 14.562 14.755 ;
     RECT  13.215 14.755 14.778 14.989 ;
     RECT  13.215 14.989 14.85 15.061 ;
     RECT  15.624 12.551 18.897 15.061 ;
     RECT  13.215 15.061 18.897 15.115 ;
     RECT  19.62 14.719 20.502 15.115 ;
     RECT  0.036 14.285 0.162 15.148 ;
     RECT  0.036 15.148 0.198 15.457 ;
     RECT  13.215 15.115 20.502 15.557 ;
     RECT  2.304 14.405 10.998 15.565 ;
     RECT  2.304 15.565 11.106 15.755 ;
     RECT  13.215 15.557 20.466 15.835 ;
     RECT  21.456 14.347 21.51 15.835 ;
     RECT  2.412 15.755 11.106 16.033 ;
     RECT  11.988 15.331 12.006 16.105 ;
     RECT  21.384 15.835 21.51 16.171 ;
     RECT  2.412 16.033 11.142 16.259 ;
     RECT  13.068 15.835 20.466 16.267 ;
     RECT  21.312 16.171 21.51 16.301 ;
     RECT  12.924 16.267 20.466 16.363 ;
     RECT  11.988 16.105 12.15 16.367 ;
     RECT  0.036 15.457 0.558 16.555 ;
     RECT  12.924 16.363 20.502 16.637 ;
     RECT  2.412 16.259 11.07 16.645 ;
     RECT  2.304 16.645 11.07 16.709 ;
     RECT  12.924 16.637 20.466 16.709 ;
     RECT  2.304 16.709 3.15 16.781 ;
     RECT  21.384 16.301 21.51 16.799 ;
     RECT  15.624 16.709 20.466 16.835 ;
     RECT  11.988 16.367 12.114 16.879 ;
     RECT  15.624 16.835 20.43 16.943 ;
     RECT  21.384 16.799 21.474 17.035 ;
     RECT  2.34 16.781 3.15 17.069 ;
     RECT  0.036 16.555 0.666 17.083 ;
     RECT  3.96 16.709 11.07 17.117 ;
     RECT  3.96 17.117 11.034 17.141 ;
     RECT  3.96 17.141 10.998 17.213 ;
     RECT  0.036 17.083 0.774 17.309 ;
     RECT  11.88 16.879 12.114 17.419 ;
     RECT  12.924 16.709 14.85 17.419 ;
     RECT  11.88 17.419 14.85 17.611 ;
     RECT  15.624 16.943 20.322 17.611 ;
     RECT  3.996 17.213 10.998 17.717 ;
     RECT  2.34 17.069 2.862 17.761 ;
     RECT  21.276 17.035 21.474 17.806 ;
     RECT  21.24 17.806 21.582 17.885 ;
     RECT  0.036 17.309 0.414 18.157 ;
     RECT  2.304 17.761 2.862 18.235 ;
     RECT  0.036 18.157 0.558 18.317 ;
     RECT  21.276 17.885 21.582 18.667 ;
     RECT  2.304 18.235 3.258 18.725 ;
     RECT  21.24 18.667 21.582 18.725 ;
     RECT  21.348 18.725 21.582 18.797 ;
     RECT  3.996 17.717 10.962 18.841 ;
     RECT  2.415 18.725 3.258 18.931 ;
     RECT  3.996 18.841 10.998 18.931 ;
     RECT  21.42 18.797 21.582 19.037 ;
     RECT  11.88 17.611 20.322 19.051 ;
     RECT  11.88 19.051 20.502 19.139 ;
     RECT  0.036 18.317 0.414 19.309 ;
     RECT  15.192 19.139 20.502 19.679 ;
     RECT  15.192 19.679 20.286 19.769 ;
     RECT  2.415 18.931 10.998 19.885 ;
     RECT  15.192 19.769 16.506 20.039 ;
     RECT  17.352 19.769 20.286 20.039 ;
     RECT  0.036 19.309 0.558 20.045 ;
     RECT  11.88 19.139 14.238 20.119 ;
     RECT  15.192 20.039 16.254 20.119 ;
     RECT  2.304 19.885 10.998 20.219 ;
     RECT  11.88 20.119 16.254 20.219 ;
     RECT  15.192 20.219 16.254 20.849 ;
     RECT  11.88 20.219 14.238 20.965 ;
     RECT  2.304 20.219 7.074 21.091 ;
     RECT  7.815 20.219 10.998 21.091 ;
     RECT  2.304 21.091 10.998 21.101 ;
     RECT  11.88 20.965 14.274 21.299 ;
     RECT  17.352 20.039 20.214 21.389 ;
     RECT  17.352 21.389 19.674 21.505 ;
     RECT  11.88 21.299 14.238 21.659 ;
     RECT  17.172 21.505 19.674 21.659 ;
     RECT  2.34 21.101 10.998 21.835 ;
     RECT  2.304 21.835 10.998 22.009 ;
     RECT  11.88 21.659 13.95 22.009 ;
     RECT  2.304 22.009 13.95 22.115 ;
     RECT  17.352 21.659 19.674 22.199 ;
     RECT  0.036 20.045 0.414 22.207 ;
     RECT  0.036 22.207 0.558 22.253 ;
     RECT  15.192 20.849 16.197 22.315 ;
     RECT  4.212 22.115 13.95 22.469 ;
     RECT  2.304 22.115 3.474 22.613 ;
     RECT  12.492 22.469 13.95 23.009 ;
     RECT  14.832 22.315 16.197 23.009 ;
     RECT  0.036 22.253 0.414 23.131 ;
     RECT  0.036 23.131 0.558 23.189 ;
     RECT  21.564 19.037 21.582 23.189 ;
     RECT  14.832 23.009 14.994 23.279 ;
     RECT  4.212 22.469 11.394 23.419 ;
     RECT  2.304 22.613 3.258 23.701 ;
     RECT  4.176 23.419 11.394 23.701 ;
     RECT  2.304 23.701 11.394 23.819 ;
     RECT  4.068 23.819 11.394 23.899 ;
     RECT  4.068 23.899 11.43 23.999 ;
     RECT  14.832 23.279 14.85 24.197 ;
     RECT  17.352 22.199 17.37 24.205 ;
     RECT  18.18 22.199 19.674 24.205 ;
     RECT  17.136 24.205 19.674 24.269 ;
     RECT  2.304 23.819 3.258 24.275 ;
     RECT  17.136 24.269 19.206 24.359 ;
     RECT  17.136 24.359 17.442 24.475 ;
     RECT  17.1 24.475 17.442 24.737 ;
     RECT  15.915 23.009 16.197 24.745 ;
     RECT  17.136 24.737 17.442 24.809 ;
     RECT  2.304 24.275 2.898 25.051 ;
     RECT  4.068 23.999 10.797 25.051 ;
     RECT  2.304 25.051 10.797 25.169 ;
     RECT  15.372 24.745 16.197 25.169 ;
     RECT  2.304 25.169 8.55 25.313 ;
     RECT  2.34 25.313 8.55 25.439 ;
     RECT  9.288 25.169 10.797 25.439 ;
     RECT  2.34 25.439 2.697 25.475 ;
     RECT  3.996 25.439 8.55 25.475 ;
     RECT  3.996 25.475 4.338 25.745 ;
     RECT  4.32 25.745 4.338 25.817 ;
     RECT  13.215 23.009 13.95 27.059 ;
     RECT  18.18 24.359 18.897 27.329 ;
     RECT  4.104 27.211 4.122 27.337 ;
     RECT  5.115 25.475 5.397 27.337 ;
     RECT  4.104 27.337 5.397 27.481 ;
     RECT  6.12 25.475 8.55 27.481 ;
     RECT  2.415 25.475 2.697 27.571 ;
     RECT  4.104 27.481 8.55 27.599 ;
     RECT  4.104 27.599 8.478 27.643 ;
     RECT  2.415 27.571 3.042 27.691 ;
     RECT  2.412 27.691 3.042 27.743 ;
     RECT  2.415 27.743 3.042 27.751 ;
     RECT  2.415 27.751 3.258 27.835 ;
     RECT  3.996 27.643 8.478 27.835 ;
     RECT  2.415 27.835 8.478 27.869 ;
     RECT  9.792 25.439 10.797 27.869 ;
     RECT  2.415 27.869 5.634 27.875 ;
     RECT  2.415 27.875 2.79 27.917 ;
     RECT  17.424 24.809 17.442 28.139 ;
     RECT  3.996 27.875 5.634 28.157 ;
     RECT  6.732 27.869 8.097 28.157 ;
     RECT  0.036 23.189 0.414 28.175 ;
     RECT  3.996 28.157 5.397 28.301 ;
     RECT  6.804 28.157 8.097 28.409 ;
     RECT  9.648 27.913 9.666 28.409 ;
     RECT  0.108 28.175 0.414 28.481 ;
     RECT  0.108 28.481 0.198 28.493 ;
     RECT  0.108 28.493 0.126 28.589 ;
     RECT  6.804 28.409 6.822 28.679 ;
     RECT  3.996 28.301 4.014 28.715 ;
     RECT  2.415 27.917 2.697 29.987 ;
     RECT  5.115 28.301 5.397 29.987 ;
     RECT  7.815 28.409 8.097 29.987 ;
     RECT  10.515 27.869 10.797 29.987 ;
     RECT  13.215 27.059 13.497 29.987 ;
     RECT  15.915 25.169 16.197 29.987 ;
     RECT  18.615 27.329 18.897 29.987 ;
     RECT  2.415 29.987 2.505 30.257 ;
     RECT  5.115 29.987 5.205 30.257 ;
     RECT  7.815 29.987 7.905 30.257 ;
     RECT  10.515 29.987 10.605 30.257 ;
     RECT  13.215 29.987 13.305 30.257 ;
     RECT  15.915 29.987 16.005 30.257 ;
     RECT  18.615 29.987 18.705 30.257 ;
    LAYER M4 ;
     RECT  0.06 13.296 0.137 25.512 ;
     RECT  0.06 27.696 0.137 28.584 ;
     RECT  0.137 27.696 0.209 28.488 ;
     RECT  0.137 13.344 2.408 25.512 ;
     RECT  0.209 27.696 2.408 28.44 ;
     RECT  2.408 2.148 2.512 30.252 ;
     RECT  2.512 2.418 2.704 29.982 ;
     RECT  2.704 13.344 2.729 25.512 ;
     RECT  2.704 27.6 4.025 28.44 ;
     RECT  2.729 13.44 4.273 25.512 ;
     RECT  4.273 13.056 4.625 25.512 ;
     RECT  4.625 12.912 5.108 25.512 ;
     RECT  4.025 27.6 5.108 28.296 ;
     RECT  5.108 2.148 5.212 30.252 ;
     RECT  5.212 2.418 5.404 29.982 ;
     RECT  5.404 20.592 5.501 24.12 ;
     RECT  5.501 20.928 5.537 24.12 ;
     RECT  5.537 21.072 5.645 24.12 ;
     RECT  5.645 23.232 5.699 24.12 ;
     RECT  5.404 13.056 5.753 19.608 ;
     RECT  5.699 23.376 5.789 24.12 ;
     RECT  5.753 18.528 5.861 19.608 ;
     RECT  5.753 13.056 5.969 17.16 ;
     RECT  5.861 18.528 5.969 19.032 ;
     RECT  5.404 25.44 6.329 25.896 ;
     RECT  5.645 21.072 6.437 22.2 ;
     RECT  5.789 23.376 6.581 24.072 ;
     RECT  5.404 28.128 6.721 28.152 ;
     RECT  5.969 15.072 6.761 17.16 ;
     RECT  6.761 15.072 6.797 16.968 ;
     RECT  6.329 25.872 6.803 25.896 ;
     RECT  6.721 27.36 6.805 28.152 ;
     RECT  6.797 15.072 6.956 16.872 ;
     RECT  6.956 15.024 7.009 16.872 ;
     RECT  5.969 19.008 7.117 19.032 ;
     RECT  7.117 18.768 7.369 19.032 ;
     RECT  6.577 10.704 7.513 10.728 ;
     RECT  5.969 13.056 7.573 13.944 ;
     RECT  7.009 14.928 7.573 16.872 ;
     RECT  7.369 18 7.657 19.032 ;
     RECT  7.513 10.656 7.765 10.728 ;
     RECT  7.765 10.128 7.808 10.728 ;
     RECT  7.573 13.056 7.808 16.872 ;
     RECT  7.657 18 7.808 19.8 ;
     RECT  6.437 21.168 7.808 22.2 ;
     RECT  6.581 23.376 7.808 23.928 ;
     RECT  6.805 28.128 7.808 28.152 ;
     RECT  7.808 2.148 7.912 30.252 ;
     RECT  7.912 2.418 8.104 29.982 ;
     RECT  8.104 19.776 8.243 22.056 ;
     RECT  8.243 20.544 8.281 22.056 ;
     RECT  8.104 25.104 8.281 25.128 ;
     RECT  8.281 21.024 8.345 22.056 ;
     RECT  8.345 21.12 8.381 22.056 ;
     RECT  8.104 18 8.417 18.744 ;
     RECT  8.104 23.376 8.531 23.928 ;
     RECT  8.381 21.552 8.633 21.672 ;
     RECT  8.104 15.456 9.155 16.872 ;
     RECT  8.104 8.736 9.169 8.76 ;
     RECT  8.104 10.128 9.169 10.728 ;
     RECT  8.531 23.904 9.173 23.928 ;
     RECT  8.104 13.056 9.277 13.944 ;
     RECT  8.417 18.72 9.529 18.744 ;
     RECT  9.349 7.68 9.565 7.704 ;
     RECT  9.155 16.32 9.601 16.872 ;
     RECT  9.529 17.952 9.601 18.744 ;
     RECT  9.601 16.32 9.781 18.744 ;
     RECT  9.565 7.152 9.925 7.704 ;
     RECT  9.169 8.736 9.925 10.728 ;
     RECT  9.925 4.944 10.508 4.968 ;
     RECT  9.925 7.152 10.508 10.728 ;
     RECT  9.277 12.528 10.508 13.944 ;
     RECT  10.249 14.928 10.508 14.952 ;
     RECT  9.781 16.32 10.508 19.56 ;
     RECT  8.633 21.552 10.508 21.576 ;
     RECT  10.508 2.148 10.612 30.252 ;
     RECT  10.612 2.418 10.804 29.982 ;
     RECT  10.804 16.32 10.829 19.08 ;
     RECT  10.829 16.32 11.081 18.984 ;
     RECT  11.081 16.32 12.085 16.344 ;
     RECT  11.081 17.616 12.085 18.984 ;
     RECT  12.085 16.32 13.057 18.984 ;
     RECT  10.804 4.8 13.208 4.824 ;
     RECT  10.804 7.056 13.208 10.728 ;
     RECT  10.804 13.392 13.208 13.944 ;
     RECT  13.057 15.84 13.208 18.984 ;
     RECT  13.208 2.148 13.312 30.252 ;
     RECT  13.312 2.418 13.504 29.982 ;
     RECT  13.504 7.056 14.533 10.728 ;
     RECT  13.504 4.8 14.821 4.824 ;
     RECT  14.533 6.96 14.821 10.728 ;
     RECT  14.821 4.704 14.861 4.824 ;
     RECT  14.861 4.704 15.908 4.728 ;
     RECT  14.821 6.864 15.908 10.728 ;
     RECT  13.504 13.392 15.908 13.944 ;
     RECT  13.504 15.84 15.908 18.984 ;
     RECT  15.908 2.148 16.012 30.252 ;
     RECT  16.012 2.418 16.204 29.982 ;
     RECT  16.204 4.56 16.913 4.728 ;
     RECT  16.204 6.864 17.629 10.728 ;
     RECT  16.204 11.952 17.629 11.976 ;
     RECT  16.204 13.392 17.629 14.136 ;
     RECT  17.629 13.392 18.169 14.472 ;
     RECT  17.629 6.864 18.205 11.976 ;
     RECT  18.169 13.152 18.205 14.472 ;
     RECT  16.204 15.84 18.385 18.984 ;
     RECT  18.385 15.792 18.493 18.984 ;
     RECT  16.913 4.56 18.608 4.584 ;
     RECT  18.205 6.864 18.608 14.472 ;
     RECT  18.493 15.792 18.608 19.032 ;
     RECT  18.608 2.148 18.712 30.252 ;
     RECT  18.712 2.418 18.904 29.982 ;
     RECT  18.904 3.888 20.473 4.584 ;
     RECT  18.904 6.864 20.473 19.032 ;
     RECT  20.473 3.792 21.445 4.584 ;
     RECT  21.445 3.792 21.564 4.68 ;
     RECT  20.473 6.864 21.564 19.08 ;
    LAYER M5 ;
     RECT  2.4 2.137 2.52 2.151 ;
     RECT  5.1 2.137 5.22 2.151 ;
     RECT  7.8 2.137 7.92 2.151 ;
     RECT  10.5 2.137 10.62 2.151 ;
     RECT  13.2 2.137 13.32 2.151 ;
     RECT  15.9 2.137 16.02 2.151 ;
     RECT  18.6 2.137 18.72 2.151 ;
     RECT  10.5 2.151 10.812 4.933 ;
     RECT  5.1 2.151 5.412 12.901 ;
     RECT  9.936 4.933 10.812 13.045 ;
     RECT  7.8 2.151 8.112 13.141 ;
     RECT  9.12 13.045 10.812 13.283 ;
     RECT  0.144 13.333 0.168 13.619 ;
     RECT  4.656 12.901 5.412 13.811 ;
     RECT  2.4 2.151 2.712 14.677 ;
     RECT  2.4 14.677 3.288 14.867 ;
     RECT  7.584 13.141 8.112 15.013 ;
     RECT  5.1 13.811 5.412 15.637 ;
     RECT  5.1 15.637 5.592 15.925 ;
     RECT  7.008 15.013 8.112 16.019 ;
     RECT  2.4 14.867 2.712 16.021 ;
     RECT  2.4 16.021 2.808 16.163 ;
     RECT  21.408 16.021 21.432 16.307 ;
     RECT  7.68 16.019 8.112 16.595 ;
     RECT  9.12 13.283 9.144 16.595 ;
     RECT  5.1 15.925 5.688 16.643 ;
     RECT  5.1 16.643 5.592 18.085 ;
     RECT  4.992 18.085 5.592 18.179 ;
     RECT  4.992 18.179 5.412 19.475 ;
     RECT  7.8 16.595 8.112 19.765 ;
     RECT  7.8 19.765 8.232 20.579 ;
     RECT  5.1 19.475 5.412 21.253 ;
     RECT  7.8 20.579 8.112 21.637 ;
     RECT  0.144 21.733 0.168 21.923 ;
     RECT  5.1 21.253 5.688 23.411 ;
     RECT  7.8 21.637 8.52 23.411 ;
     RECT  2.4 16.163 2.712 23.893 ;
     RECT  5.1 23.411 5.544 24.131 ;
     RECT  7.8 23.411 8.232 25.139 ;
     RECT  6.768 25.861 6.792 27.395 ;
     RECT  2.4 23.893 4.008 27.635 ;
     RECT  2.4 27.635 3.288 27.875 ;
     RECT  2.4 27.875 2.712 30.249 ;
     RECT  5.1 24.131 5.412 30.249 ;
     RECT  7.8 25.139 8.112 30.249 ;
     RECT  10.5 13.283 10.812 30.249 ;
     RECT  13.2 2.151 13.512 30.249 ;
     RECT  15.9 2.151 16.212 30.249 ;
     RECT  18.6 2.151 18.912 30.249 ;
     RECT  2.4 30.249 2.52 30.263 ;
     RECT  5.1 30.249 5.22 30.263 ;
     RECT  7.8 30.249 7.92 30.263 ;
     RECT  10.5 30.249 10.62 30.263 ;
     RECT  13.2 30.249 13.32 30.263 ;
     RECT  15.9 30.249 16.02 30.263 ;
     RECT  18.6 30.249 18.72 30.263 ;
  END
END hbfd_lh_136_WE
END LIBRARY
